VERSION 5.7 ;
  NOWIREEXTENSIONATPIN ON ;
  DIVIDERCHAR "/" ;
  BUSBITCHARS "[]" ;
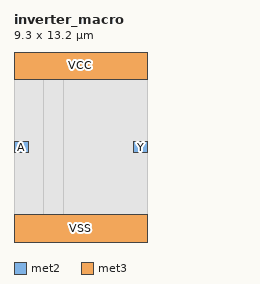
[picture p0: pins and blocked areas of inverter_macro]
MACRO inverter_macro
  CLASS BLOCK ;
  FOREIGN inverter_macro ;
  ORIGIN 0.000 0.000 ;
  SIZE 9.300 BY 13.200 ;
  PIN A
    DIRECTION INPUT ;
    USE SIGNAL ;
    ANTENNAGATEAREA 1.520000 ;
    PORT
      LAYER met2 ;
        RECT 0.000 6.200 1.000 7.000 ;
    END
  END A
  PIN Y
    DIRECTION OUTPUT ;
    USE SIGNAL ;
    ANTENNADIFFAREA 6.460000 ;
    PORT
      LAYER met2 ;
        RECT 8.300 6.200 9.300 7.000 ;
    END
  END Y
  PIN VCC
    DIRECTION INOUT ;
    USE POWER ;
    PORT
      LAYER met3 ;
        RECT 0.000 11.300 9.300 13.200 ;
    END
  END VCC
  PIN VSS
    DIRECTION INOUT ;
    USE GROUND ;
    PORT
      LAYER met3 ;
        RECT 0.000 0.000 9.300 1.900 ;
    END
  END VSS
  OBS
      LAYER nwell ;
        RECT 1.000 2.800 8.300 10.400 ;
      LAYER li1 ;
        RECT 0.000 0.000 9.300 13.200 ;
      LAYER met1 ;
        RECT 0.000 0.000 9.300 13.200 ;
      LAYER met2 ;
        RECT 2.050 0.000 3.450 13.200 ;
  END
END inverter_macro
END LIBRARY

